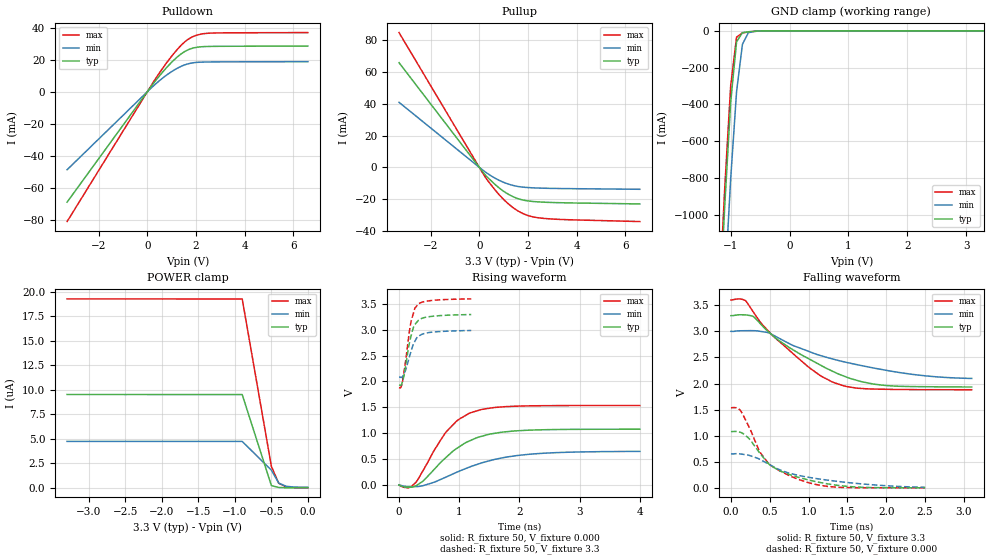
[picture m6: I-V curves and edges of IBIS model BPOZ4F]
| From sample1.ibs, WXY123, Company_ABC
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|   Model BPOZ4F
[Model]   BPOZ4F
Model_type   3-state
Polarity   Non-Inverting
Enable   Active-High
Vmeas   = 1.65V
Cref   = 10pF
Vref   = 0V
Rref   = 1Mohms
C_comp   1.27pF  NA   NA
[Temperature Range]   25   125   0
[Voltage Range]   3.3V   3.0V   3.6V
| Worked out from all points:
|   slope of the pulldown table from 0 to 0.495 V, typ, clamps not added: 50.4 ohm
|   slope of the pullup table from 0 to 0.495 V, typ, clamps not added: 57.6 ohm
|   GND clamp passes 1 mA (typ) near -0.52 V on its own axis
|   rising waveform, R_fixture 50, V_fixture 0.000: 20-80 % time 677ps typ, 961ps min, 539ps max; typ from 0 V to 1.08 V
|   rising waveform, R_fixture 50, V_fixture 3.3: 20-80 % time 137ps typ, 154ps min, 135ps max; typ from 1.93 V to 3.29 V
|   falling waveform, R_fixture 50, V_fixture 3.3: 20-80 % time 893ps typ, 1.23ns min, 742ps max; typ from 3.3 V to 1.93 V
|   falling waveform, R_fixture 50, V_fixture 0.000: 20-80 % time 561ps typ, 893ps min, 442ps max; typ from 1.08 V to 0.001 V
[Pulldown]
| voltage   I(typ)   I(min)   I(max)
-3.3V     -68.87mA   -48.66mA   -80.98mA
400mV     8.038mA    5.623mA    9.519mA
800mV     15.18mA    10.46mA    18.18mA
1.1V      19.84mA    13.49mA    24.03mA
1.4V      23.69mA    15.89mA    29.11mA
1.6V      25.58mA    17.05mA    31.83mA
2V        27.61mA    18.24mA    35.09mA
2.5V      28.21mA    18.53mA    36.45mA
6.6V      28.45mA    18.72mA    36.86mA
[Pullup]
| voltage   I(typ)   I(min)   I(max)
-3.3V     65.98mA    40.99mA    84.97mA
200mV     -3.908mA   -2.396mA   -5.05mA
300mV     -5.71mA    -3.492mA   -7.408mA
800mV     -12.78mA   -8.056mA   -16.97mA
1.3V      -17.84mA   -11.05mA   -24.36mA
1.6V      -19.78mA   -12.08mA   -27.56mA
1.9V      -20.93mA   -12.63mA   -29.83mA
2.5V      -21.85mA   -13.09mA   -31.95mA
3.5V      -22.36mA   -13.39mA   -32.95mA
6.6V      -23.08mA   -13.84mA   -34.19mA
[GND Clamp]
|  voltage   I(typ)   I(min)   I(max)
-3.3V     -16.58A    -16.78A    -16.66A
-1.2V     -1.583A    -2.021A    -1.492A
-1.1V     -947.2mA   -1.389A    -849.8mA
-1V       -387.9mA   -804.9mA   -298.8mA
-900mV    -60.13mA   -330.4mA   -34.44mA
-800mV    -9.812mA   -73.16mA   -11.08mA
-700mV    -5.132mA   -10.39mA   -6.64mA
-500mV    -584.2uA   -1.131mA   -841uA
3.3V      2.184nA    165.1nA    7.987nA
[POWER Clamp]
|  voltage   I(typ)   I(min)   I(max)
-3.3V     9.534uA    4.747uA    19.3uA
-900mV    9.525uA    4.742uA    19.28uA
-500mV    228.3nA    1.803uA    2.194uA
-400mV    40.87nA    494.6nA    467.2nA
-300mV    10.06nA    165.1nA    110.5nA
0V        2.184nA    62.48nA    8.575nA
| variable   typ   min   max
[Ramp]
dV/dt_r  0.64626V/0.676621ns   0.38896V/0.960544ns   0.92064V/0.538701ns
dV/dt_f  0.82026V/0.89276ns   0.54192V/1.22712ns   1.03164V/0.741504ns
R_load   = 50
[Rising Waveform]
R_fixture   = 50
V_fixture   = 0.000
V_fixture_min   = 0.000
V_fixture_max   = 0.000
| time   V(typ)   V(min)   V(max)
0s        0V         0V         0V
160ps     -42.07mV   -30.65mV   -55.54mV
280ps     -17.48mV   -31.69mV   49.73mV
400ps     75.39mV    -13.54mV   280.3mV
760ps     509.5mV    142mV      990.7mV
960ps     706mV      246.6mV    1.237V
1.2ns     865.9mV    359.2mV    1.399V
1.52ns    984.6mV    472.9mV    1.485V
2.2ns     1.06V      596.6mV    1.528V
4ns       1.077V     648.3mV    1.534V
[Rising Waveform]
R_fixture   = 50
V_fixture   = 3.3
V_fixture_min   = 3.0
V_fixture_max   = 3.6
| time   V(typ)   V(min)   V(max)
0s        1.93V      2.083V     1.881V
24ps      1.924V     2.079V     1.873V
60ps      2.005V     2.094V     2.01V
120ps     2.377V     2.254V     2.486V
168ps     2.717V     2.456V     2.932V
204ps     2.893V     2.595V     3.176V
264ps     3.099V     2.776V     3.414V
312ps     3.166V     2.862V     3.483V
516ps     3.252V     2.946V     3.559V
1.2ns     3.291V     2.983V     3.594V
[Falling Waveform]
R_fixture   = 50
V_fixture   = 3.3
V_fixture_min   = 3.0
V_fixture_max   = 3.6
| time   V(typ)   V(min)   V(max)
0s        3.3V       3V         3.6V
186ps     3.316V     3.012V     3.591V
279ps     3.293V     3.013V     3.389V
496ps     2.974V     2.966V     2.982V
837ps     2.612V     2.707V     2.523V
1.147ns   2.357V     2.538V     2.155V
1.333ns   2.217V     2.461V     2.014V
1.612ns   2.064V     2.365V     1.913V
1.984ns   1.963V     2.257V     1.889V
3.1ns     1.933V     2.097V     1.881V
[Falling Waveform]
R_fixture   = 50
V_fixture   = 0.000
V_fixture_min   = 0.000
V_fixture_max   = 0.000
| time   V(typ)   V(min)   V(max)
0s        1.077V     650.8mV    1.534V
75ps      1.08V      654.9mV    1.535V
125ps     1.063V     649.5mV    1.478V
225ps     957.4mV    627.5mV    1.192V
375ps     659.7mV    543.2mV    679.6mV
500ps     441.3mV    442.7mV    441.1mV
850ps     210.3mV    245.3mV    173.4mV
1.125ns   109.2mV    172.7mV    54.81mV
1.375ns   48.08mV    123.5mV    11.27mV
2.5ns     969.3uV    10.2mV     227.5uV
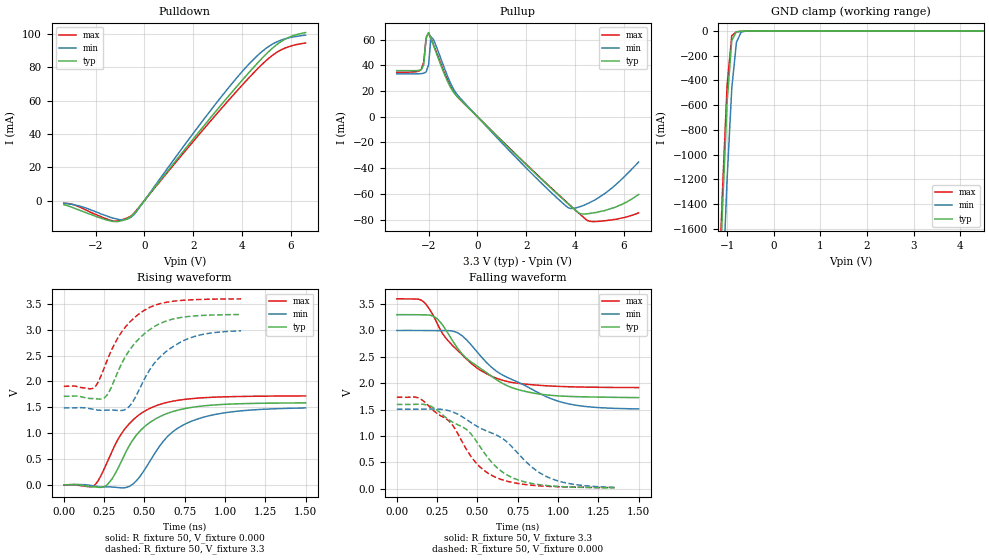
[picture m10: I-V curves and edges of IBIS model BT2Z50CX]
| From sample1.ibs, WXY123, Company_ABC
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|   Model BT2Z50CX
[Model]   BT2Z50CX
Model_type   I/O
Polarity   Non-Inverting
Enable   Active-High
Vinl   = 0.8V
Vinh   = 2.0V
Vmeas   = 1.65V
Cref   = 1.0pF
Vref   = 0V
Rref   = 1Mohms
C_comp   1.26pF  NA   NA
[Temperature Range]   25   125   0
[Voltage Range]   3.3V   3.0V   3.6V
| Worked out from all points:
|   slope of the pulldown table from 0 to 0.495 V, typ, clamps not added: 53.3 ohm
|   slope of the pullup table from 0 to 0.495 V, typ, clamps not added: 52.7 ohm
|   GND clamp passes 1 mA (typ) near -0.54 V on its own axis
|   rising waveform, R_fixture 50, V_fixture 0.000: 20-80 % time 229ps typ, 260ps min, 222ps max; typ from 0 V to 1.58 V
|   rising waveform, R_fixture 50, V_fixture 3.3: 20-80 % time 209ps typ, 223ps min, 199ps max; typ from 1.71 V to 3.29 V
|   falling waveform, R_fixture 50, V_fixture 3.3: 20-80 % time 322ps typ, 416ps min, 286ps max; typ from 3.3 V to 1.73 V
|   falling waveform, R_fixture 50, V_fixture 0.000: 20-80 % time 312ps typ, 394ps min, 268ps max; typ from 1.6 V to 0.014 V
[Pulldown]
| voltage   I(typ)   I(min)   I(max)
-3.3V     -2.4mA     -1.6mA     -1.5mA
-2.6V     -6.1mA     -3.5mA     -4.2mA
-1.3V     -12.5mA    -10.5mA    -12.2mA
-800mV    -11.51mA   -11.45mA   -10.97mA
-500mV    -9.074mA   -9.476mA   -8.684mA
2.6V      47.85mA    52.05mA    45.93mA
3.6V      65.43mA    70.57mA    62.78mA
4.3V      77.25mA    82.31mA    74.07mA
4.9V      86.76mA    90.57mA    83mA
5.5V      94.6mA     95.89mA    89.78mA
6V        98.6mA     98.08mA    92.87mA
6.6V      101mA      99.42mA    94.71mA
[Pullup]
| voltage   I(typ)   I(min)   I(max)
-3.3V     35.84mA    33.36mA    34.61mA
-2.3V     36.53mA    33.51mA    36.86mA
-2.2V     40.17mA    33.81mA    42.35mA
-2.1V     61.77mA    34.85mA    61.19mA
-2V       65.44mA    40.34mA    65.17mA
-1.9V     60.79mA    62.16mA    60.85mA
-1.3V     30.81mA    35.17mA    32.05mA
-900mV    17.21mA    19.07mA    17.33mA
3.8V      -69.24mA   -71.39mA   -69.05mA
4.2V      -75.43mA   -70mA      -75.89mA
4.7V      -75mA      -65.8mA    -81.6mA
6.6V      -60.5mA    -35.3mA    -74.8mA
[GND Clamp]
|  voltage   I(typ)   I(min)   I(max)
-3.3V     -26.2A     -26.68A    -26.15A
-1.2V     -2.457A    -3.123A    -2.307A
-1.1V     -1.452A    -2.119A    -1.3A
-1V       -574.7mA   -1.197A    -440mA
-900mV    -76.63mA   -463mA     -38.82mA
-800mV    -7.368mA   -92.58mA   -7.945mA
-700mV    -3.455mA   -10.36mA   -4.753mA
-500mV    -491uA     -890.9uA   -717.6uA
6.6V      3.749nA    84.35nA    16.71nA
| variable   typ   min   max
[Ramp]
dV/dt_r  0.95034V/0.229117ns   0.89154V/0.259917ns   1.03134V/0.221514ns
dV/dt_f  0.94434V/0.321706ns   0.89334V/0.416296ns   1.00998V/0.285923ns
R_load   = 50
[Rising Waveform]
R_fixture   = 50
V_fixture   = 0.000
V_fixture_min   = 0.000
V_fixture_max   = 0.000
| time   V(typ)   V(min)   V(max)
0s        0V         0V         0V
180ps     -38.98mV   -19.79mV   -31.87mV
255ps     -31.69mV   -41.02mV   338.2mV
345ps     372.5mV    -57.1mV    926.6mV
420ps     828.3mV    -5.029mV   1.226V
570ps     1.276V     634.1mV    1.526V
690ps     1.429V     1.057V     1.624V
855ps     1.522V     1.296V     1.681V
1.095ns   1.567V     1.428V     1.708V
1.5ns     1.584V     1.486V     1.719V
[Rising Waveform]
R_fixture   = 50
V_fixture   = 3.3
V_fixture_min   = 3.0
V_fixture_max   = 3.6
| time   V(typ)   V(min)   V(max)
0s        1.712V     1.487V     1.905V
187ps     1.667V     1.457V     1.877V
253ps     1.684V     1.441V     2.28V
319ps     2.062V     1.442V     2.749V
396ps     2.549V     1.486V     3.102V
429ps     2.693V     1.61V      3.206V
528ps     2.988V     2.2V       3.423V
627ps     3.158V     2.557V     3.524V
759ps     3.25V      2.81V      3.572V
1.1ns     3.294V     2.979V     3.596V
[Falling Waveform]
R_fixture   = 50
V_fixture   = 3.3
V_fixture_min   = 3.0
V_fixture_max   = 3.6
| time   V(typ)   V(min)   V(max)
0s        3.3V       3V         3.6V
165ps     3.296V     3V         3.547V
255ps     3.21V      2.997V     3.102V
300ps     3.03V      2.998V     2.873V
375ps     2.672V     2.96V      2.629V
495ps     2.33V      2.604V     2.294V
615ps     2.073V     2.234V     2.097V
780ps     1.856V     1.978V     1.987V
1.035ns   1.754V     1.629V     1.936V
1.5ns     1.726V     1.511V     1.917V
[Falling Waveform]
R_fixture   = 50
V_fixture   = 0.000
V_fixture_min   = 0.000
V_fixture_max   = 0.000
| time   V(typ)   V(min)   V(max)
0s        1.597V     1.506V     1.733V
135ps     1.601V     1.506V     1.718V
243ps     1.506V     1.509V     1.44V
337.5ps   1.276V     1.464V     1.235V
432ps     1.122V     1.312V     743.6mV
513ps     809.8mV    1.155V     419.2mV
621ps     398.3mV    1.012V     203.6mV
756ps     160.1mV    654.1mV    93.93mV
945ps     53.52mV    205.6mV    41.78mV
1.35ns    13.86mV    23.24mV    17.46mV
